# PLANNED PHY PG PROTOTYPE ONLY: no signoff or released-view claim
VERSION 5.8 ;
BUSBITCHARS "[]" ;
DIVIDERCHAR "/" ;
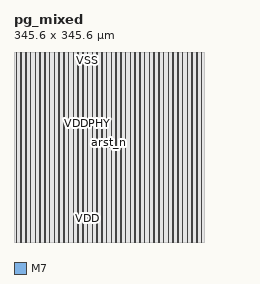
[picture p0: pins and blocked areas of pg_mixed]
MACRO pg_mixed
  CLASS BLOCK ;
  ORIGIN 0 0 ;
  SIZE 345.6000 BY 345.6000 ;
  PIN clk
    DIRECTION INPUT ;
    USE CLOCK ;
    PORT
      LAYER M7 ;
        RECT 172.8160 172.4480 172.8480 173.2160 ;
    END
  END clk
  PIN arst_n
    DIRECTION INPUT ;
    USE SIGNAL ;
    PORT
      LAYER M7 ;
        RECT 172.8160 181.0240 172.8480 181.7920 ;
    END
  END arst_n
  PIN VDD
    DIRECTION INOUT ;
    USE POWER ;
    PORT
      LAYER M7 ;
        RECT 3.9840 0.0000 4.2720 86.3040 ;
      LAYER M7 ;
        RECT 12.6240 0.0000 12.9120 86.3040 ;
      LAYER M7 ;
        RECT 21.2640 0.0000 21.5520 86.3040 ;
      LAYER M7 ;
        RECT 29.9040 0.0000 30.1920 86.3040 ;
      LAYER M7 ;
        RECT 38.5440 0.0000 38.8320 86.3040 ;
      LAYER M7 ;
        RECT 47.1840 0.0000 47.4720 86.3040 ;
      LAYER M7 ;
        RECT 55.8240 0.0000 56.1120 86.3040 ;
      LAYER M7 ;
        RECT 64.4640 0.0000 64.7520 86.3040 ;
      LAYER M7 ;
        RECT 73.1040 0.0000 73.3920 86.3040 ;
      LAYER M7 ;
        RECT 81.7440 0.0000 82.0320 86.3040 ;
      LAYER M7 ;
        RECT 90.3840 0.0000 90.6720 86.3040 ;
      LAYER M7 ;
        RECT 99.0240 0.0000 99.3120 86.3040 ;
      LAYER M7 ;
        RECT 107.6640 0.0000 107.9520 86.3040 ;
      LAYER M7 ;
        RECT 116.3040 0.0000 116.5920 86.3040 ;
      LAYER M7 ;
        RECT 124.9440 0.0000 125.2320 86.3040 ;
      LAYER M7 ;
        RECT 133.5840 0.0000 133.8720 86.3040 ;
      LAYER M7 ;
        RECT 142.2240 0.0000 142.5120 86.3040 ;
      LAYER M7 ;
        RECT 150.8640 0.0000 151.1520 86.3040 ;
      LAYER M7 ;
        RECT 159.5040 0.0000 159.7920 86.3040 ;
      LAYER M7 ;
        RECT 168.1440 0.0000 168.4320 86.3040 ;
      LAYER M7 ;
        RECT 176.7840 0.0000 177.0720 86.3040 ;
      LAYER M7 ;
        RECT 185.4240 0.0000 185.7120 86.3040 ;
      LAYER M7 ;
        RECT 194.0640 0.0000 194.3520 86.3040 ;
      LAYER M7 ;
        RECT 202.7040 0.0000 202.9920 86.3040 ;
      LAYER M7 ;
        RECT 211.3440 0.0000 211.6320 86.3040 ;
      LAYER M7 ;
        RECT 219.9840 0.0000 220.2720 86.3040 ;
      LAYER M7 ;
        RECT 228.6240 0.0000 228.9120 86.3040 ;
      LAYER M7 ;
        RECT 237.2640 0.0000 237.5520 86.3040 ;
      LAYER M7 ;
        RECT 245.9040 0.0000 246.1920 86.3040 ;
      LAYER M7 ;
        RECT 254.5440 0.0000 254.8320 86.3040 ;
      LAYER M7 ;
        RECT 263.1840 0.0000 263.4720 86.3040 ;
      LAYER M7 ;
        RECT 271.8240 0.0000 272.1120 86.3040 ;
      LAYER M7 ;
        RECT 280.4640 0.0000 280.7520 86.3040 ;
      LAYER M7 ;
        RECT 289.1040 0.0000 289.3920 86.3040 ;
      LAYER M7 ;
        RECT 297.7440 0.0000 298.0320 86.3040 ;
      LAYER M7 ;
        RECT 306.3840 0.0000 306.6720 86.3040 ;
      LAYER M7 ;
        RECT 315.0240 0.0000 315.3120 86.3040 ;
      LAYER M7 ;
        RECT 323.6640 0.0000 323.9520 86.3040 ;
      LAYER M7 ;
        RECT 332.3040 0.0000 332.5920 86.3040 ;
      LAYER M7 ;
        RECT 340.9440 0.0000 341.2320 86.3040 ;
    END
  END VDD
  PIN VDDPHY
    DIRECTION INOUT ;
    USE POWER ;
    PORT
      LAYER M7 ;
        RECT 3.9840 86.4000 4.2720 345.6000 ;
      LAYER M7 ;
        RECT 12.6240 86.4000 12.9120 345.6000 ;
      LAYER M7 ;
        RECT 21.2640 86.4000 21.5520 345.6000 ;
      LAYER M7 ;
        RECT 29.9040 86.4000 30.1920 345.6000 ;
      LAYER M7 ;
        RECT 38.5440 86.4000 38.8320 345.6000 ;
      LAYER M7 ;
        RECT 47.1840 86.4000 47.4720 345.6000 ;
      LAYER M7 ;
        RECT 55.8240 86.4000 56.1120 345.6000 ;
      LAYER M7 ;
        RECT 64.4640 86.4000 64.7520 345.6000 ;
      LAYER M7 ;
        RECT 73.1040 86.4000 73.3920 345.6000 ;
      LAYER M7 ;
        RECT 81.7440 86.4000 82.0320 345.6000 ;
      LAYER M7 ;
        RECT 90.3840 86.4000 90.6720 345.6000 ;
      LAYER M7 ;
        RECT 99.0240 86.4000 99.3120 345.6000 ;
      LAYER M7 ;
        RECT 107.6640 86.4000 107.9520 345.6000 ;
      LAYER M7 ;
        RECT 116.3040 86.4000 116.5920 345.6000 ;
      LAYER M7 ;
        RECT 124.9440 86.4000 125.2320 345.6000 ;
      LAYER M7 ;
        RECT 133.5840 86.4000 133.8720 345.6000 ;
      LAYER M7 ;
        RECT 142.2240 86.4000 142.5120 345.6000 ;
      LAYER M7 ;
        RECT 150.8640 86.4000 151.1520 345.6000 ;
      LAYER M7 ;
        RECT 159.5040 86.4000 159.7920 345.6000 ;
      LAYER M7 ;
        RECT 168.1440 86.4000 168.4320 345.6000 ;
      LAYER M7 ;
        RECT 176.7840 86.4000 177.0720 345.6000 ;
      LAYER M7 ;
        RECT 185.4240 86.4000 185.7120 345.6000 ;
      LAYER M7 ;
        RECT 194.0640 86.4000 194.3520 345.6000 ;
      LAYER M7 ;
        RECT 202.7040 86.4000 202.9920 345.6000 ;
      LAYER M7 ;
        RECT 211.3440 86.4000 211.6320 345.6000 ;
      LAYER M7 ;
        RECT 219.9840 86.4000 220.2720 345.6000 ;
      LAYER M7 ;
        RECT 228.6240 86.4000 228.9120 345.6000 ;
      LAYER M7 ;
        RECT 237.2640 86.4000 237.5520 345.6000 ;
      LAYER M7 ;
        RECT 245.9040 86.4000 246.1920 345.6000 ;
      LAYER M7 ;
        RECT 254.5440 86.4000 254.8320 345.6000 ;
      LAYER M7 ;
        RECT 263.1840 86.4000 263.4720 345.6000 ;
      LAYER M7 ;
        RECT 271.8240 86.4000 272.1120 345.6000 ;
      LAYER M7 ;
        RECT 280.4640 86.4000 280.7520 345.6000 ;
      LAYER M7 ;
        RECT 289.1040 86.4000 289.3920 345.6000 ;
      LAYER M7 ;
        RECT 297.7440 86.4000 298.0320 345.6000 ;
      LAYER M7 ;
        RECT 306.3840 86.4000 306.6720 345.6000 ;
      LAYER M7 ;
        RECT 315.0240 86.4000 315.3120 345.6000 ;
      LAYER M7 ;
        RECT 323.6640 86.4000 323.9520 345.6000 ;
      LAYER M7 ;
        RECT 332.3040 86.4000 332.5920 345.6000 ;
      LAYER M7 ;
        RECT 340.9440 86.4000 341.2320 345.6000 ;
    END
  END VDDPHY
  PIN VSS
    DIRECTION INOUT ;
    USE GROUND ;
    PORT
      LAYER M7 ;
        RECT 4.3680 0.0000 4.6560 345.6000 ;
      LAYER M7 ;
        RECT 13.0080 0.0000 13.2960 345.6000 ;
      LAYER M7 ;
        RECT 21.6480 0.0000 21.9360 345.6000 ;
      LAYER M7 ;
        RECT 30.2880 0.0000 30.5760 345.6000 ;
      LAYER M7 ;
        RECT 38.9280 0.0000 39.2160 345.6000 ;
      LAYER M7 ;
        RECT 47.5680 0.0000 47.8560 345.6000 ;
      LAYER M7 ;
        RECT 56.2080 0.0000 56.4960 345.6000 ;
      LAYER M7 ;
        RECT 64.8480 0.0000 65.1360 345.6000 ;
      LAYER M7 ;
        RECT 73.4880 0.0000 73.7760 345.6000 ;
      LAYER M7 ;
        RECT 82.1280 0.0000 82.4160 345.6000 ;
      LAYER M7 ;
        RECT 90.7680 0.0000 91.0560 345.6000 ;
      LAYER M7 ;
        RECT 99.4080 0.0000 99.6960 345.6000 ;
      LAYER M7 ;
        RECT 108.0480 0.0000 108.3360 345.6000 ;
      LAYER M7 ;
        RECT 116.6880 0.0000 116.9760 345.6000 ;
      LAYER M7 ;
        RECT 125.3280 0.0000 125.6160 345.6000 ;
      LAYER M7 ;
        RECT 133.9680 0.0000 134.2560 345.6000 ;
      LAYER M7 ;
        RECT 142.6080 0.0000 142.8960 345.6000 ;
      LAYER M7 ;
        RECT 151.2480 0.0000 151.5360 345.6000 ;
      LAYER M7 ;
        RECT 159.8880 0.0000 160.1760 345.6000 ;
      LAYER M7 ;
        RECT 168.5280 0.0000 168.8160 345.6000 ;
      LAYER M7 ;
        RECT 177.1680 0.0000 177.4560 345.6000 ;
      LAYER M7 ;
        RECT 185.8080 0.0000 186.0960 345.6000 ;
      LAYER M7 ;
        RECT 194.4480 0.0000 194.7360 345.6000 ;
      LAYER M7 ;
        RECT 203.0880 0.0000 203.3760 345.6000 ;
      LAYER M7 ;
        RECT 211.7280 0.0000 212.0160 345.6000 ;
      LAYER M7 ;
        RECT 220.3680 0.0000 220.6560 345.6000 ;
      LAYER M7 ;
        RECT 229.0080 0.0000 229.2960 345.6000 ;
      LAYER M7 ;
        RECT 237.6480 0.0000 237.9360 345.6000 ;
      LAYER M7 ;
        RECT 246.2880 0.0000 246.5760 345.6000 ;
      LAYER M7 ;
        RECT 254.9280 0.0000 255.2160 345.6000 ;
      LAYER M7 ;
        RECT 263.5680 0.0000 263.8560 345.6000 ;
      LAYER M7 ;
        RECT 272.2080 0.0000 272.4960 345.6000 ;
      LAYER M7 ;
        RECT 280.8480 0.0000 281.1360 345.6000 ;
      LAYER M7 ;
        RECT 289.4880 0.0000 289.7760 345.6000 ;
      LAYER M7 ;
        RECT 298.1280 0.0000 298.4160 345.6000 ;
      LAYER M7 ;
        RECT 306.7680 0.0000 307.0560 345.6000 ;
      LAYER M7 ;
        RECT 315.4080 0.0000 315.6960 345.6000 ;
      LAYER M7 ;
        RECT 324.0480 0.0000 324.3360 345.6000 ;
      LAYER M7 ;
        RECT 332.6880 0.0000 332.9760 345.6000 ;
      LAYER M7 ;
        RECT 341.3280 0.0000 341.6160 345.6000 ;
    END
  END VSS
  OBS
    LAYER M1 ;
      RECT 0 0 345.6000 345.6000 ;
    LAYER M2 ;
      RECT 0 0 345.6000 345.6000 ;
    LAYER M3 ;
      RECT 0 0 345.6000 345.6000 ;
    LAYER M4 ;
      RECT 0 0 345.6000 345.6000 ;
    LAYER M5 ;
      RECT 0 0 345.6000 345.6000 ;
    LAYER M6 ;
      RECT 0 0 345.6000 345.6000 ;
    LAYER M7 ;
      RECT 0.0000 0.0000 3.9840 345.6000 ;
      RECT 4.2720 0.0000 4.3680 345.6000 ;
      RECT 4.6560 0.0000 12.6240 345.6000 ;
      RECT 12.9120 0.0000 13.0080 345.6000 ;
      RECT 13.2960 0.0000 21.2640 345.6000 ;
      RECT 21.5520 0.0000 21.6480 345.6000 ;
      RECT 21.9360 0.0000 29.9040 345.6000 ;
      RECT 30.1920 0.0000 30.2880 345.6000 ;
      RECT 30.5760 0.0000 38.5440 345.6000 ;
      RECT 38.8320 0.0000 38.9280 345.6000 ;
      RECT 39.2160 0.0000 47.1840 345.6000 ;
      RECT 47.4720 0.0000 47.5680 345.6000 ;
      RECT 47.8560 0.0000 55.8240 345.6000 ;
      RECT 56.1120 0.0000 56.2080 345.6000 ;
      RECT 56.4960 0.0000 64.4640 345.6000 ;
      RECT 64.7520 0.0000 64.8480 345.6000 ;
      RECT 65.1360 0.0000 73.1040 345.6000 ;
      RECT 73.3920 0.0000 73.4880 345.6000 ;
      RECT 73.7760 0.0000 81.7440 345.6000 ;
      RECT 82.0320 0.0000 82.1280 345.6000 ;
      RECT 82.4160 0.0000 90.3840 345.6000 ;
      RECT 90.6720 0.0000 90.7680 345.6000 ;
      RECT 91.0560 0.0000 99.0240 345.6000 ;
      RECT 99.3120 0.0000 99.4080 345.6000 ;
      RECT 99.6960 0.0000 107.6640 345.6000 ;
      RECT 107.9520 0.0000 108.0480 345.6000 ;
      RECT 108.3360 0.0000 116.3040 345.6000 ;
      RECT 116.5920 0.0000 116.6880 345.6000 ;
      RECT 116.9760 0.0000 124.9440 345.6000 ;
      RECT 125.2320 0.0000 125.3280 345.6000 ;
      RECT 125.6160 0.0000 133.5840 345.6000 ;
      RECT 133.8720 0.0000 133.9680 345.6000 ;
      RECT 134.2560 0.0000 142.2240 345.6000 ;
      RECT 142.5120 0.0000 142.6080 345.6000 ;
      RECT 142.8960 0.0000 150.8640 345.6000 ;
      RECT 151.1520 0.0000 151.2480 345.6000 ;
      RECT 151.5360 0.0000 159.5040 345.6000 ;
      RECT 159.7920 0.0000 159.8880 345.6000 ;
      RECT 160.1760 0.0000 168.1440 345.6000 ;
      RECT 168.4320 0.0000 168.5280 345.6000 ;
      RECT 168.8160 0.0000 176.7840 345.6000 ;
      RECT 177.0720 0.0000 177.1680 345.6000 ;
      RECT 177.4560 0.0000 185.4240 345.6000 ;
      RECT 185.7120 0.0000 185.8080 345.6000 ;
      RECT 186.0960 0.0000 194.0640 345.6000 ;
      RECT 194.3520 0.0000 194.4480 345.6000 ;
      RECT 194.7360 0.0000 202.7040 345.6000 ;
      RECT 202.9920 0.0000 203.0880 345.6000 ;
      RECT 203.3760 0.0000 211.3440 345.6000 ;
      RECT 211.6320 0.0000 211.7280 345.6000 ;
      RECT 212.0160 0.0000 219.9840 345.6000 ;
      RECT 220.2720 0.0000 220.3680 345.6000 ;
      RECT 220.6560 0.0000 228.6240 345.6000 ;
      RECT 228.9120 0.0000 229.0080 345.6000 ;
      RECT 229.2960 0.0000 237.2640 345.6000 ;
      RECT 237.5520 0.0000 237.6480 345.6000 ;
      RECT 237.9360 0.0000 245.9040 345.6000 ;
      RECT 246.1920 0.0000 246.2880 345.6000 ;
      RECT 246.5760 0.0000 254.5440 345.6000 ;
      RECT 254.8320 0.0000 254.9280 345.6000 ;
      RECT 255.2160 0.0000 263.1840 345.6000 ;
      RECT 263.4720 0.0000 263.5680 345.6000 ;
      RECT 263.8560 0.0000 271.8240 345.6000 ;
      RECT 272.1120 0.0000 272.2080 345.6000 ;
      RECT 272.4960 0.0000 280.4640 345.6000 ;
      RECT 280.7520 0.0000 280.8480 345.6000 ;
      RECT 281.1360 0.0000 289.1040 345.6000 ;
      RECT 289.3920 0.0000 289.4880 345.6000 ;
      RECT 289.7760 0.0000 297.7440 345.6000 ;
      RECT 298.0320 0.0000 298.1280 345.6000 ;
      RECT 298.4160 0.0000 306.3840 345.6000 ;
      RECT 306.6720 0.0000 306.7680 345.6000 ;
      RECT 307.0560 0.0000 315.0240 345.6000 ;
      RECT 315.3120 0.0000 315.4080 345.6000 ;
      RECT 315.6960 0.0000 323.6640 345.6000 ;
      RECT 323.9520 0.0000 324.0480 345.6000 ;
      RECT 324.3360 0.0000 332.3040 345.6000 ;
      RECT 332.5920 0.0000 332.6880 345.6000 ;
      RECT 332.9760 0.0000 340.9440 345.6000 ;
      RECT 341.2320 0.0000 341.3280 345.6000 ;
      RECT 341.6160 0.0000 345.6000 345.6000 ;
      RECT 340.9440 86.3040 341.2320 86.4000 ;
      RECT 332.3040 86.3040 332.5920 86.4000 ;
      RECT 323.6640 86.3040 323.9520 86.4000 ;
      RECT 315.0240 86.3040 315.3120 86.4000 ;
      RECT 306.3840 86.3040 306.6720 86.4000 ;
      RECT 297.7440 86.3040 298.0320 86.4000 ;
      RECT 289.1040 86.3040 289.3920 86.4000 ;
      RECT 280.4640 86.3040 280.7520 86.4000 ;
      RECT 271.8240 86.3040 272.1120 86.4000 ;
      RECT 263.1840 86.3040 263.4720 86.4000 ;
      RECT 254.5440 86.3040 254.8320 86.4000 ;
      RECT 245.9040 86.3040 246.1920 86.4000 ;
      RECT 237.2640 86.3040 237.5520 86.4000 ;
      RECT 228.6240 86.3040 228.9120 86.4000 ;
      RECT 219.9840 86.3040 220.2720 86.4000 ;
      RECT 211.3440 86.3040 211.6320 86.4000 ;
      RECT 202.7040 86.3040 202.9920 86.4000 ;
      RECT 194.0640 86.3040 194.3520 86.4000 ;
      RECT 185.4240 86.3040 185.7120 86.4000 ;
      RECT 176.7840 86.3040 177.0720 86.4000 ;
      RECT 168.1440 86.3040 168.4320 86.4000 ;
      RECT 159.5040 86.3040 159.7920 86.4000 ;
      RECT 150.8640 86.3040 151.1520 86.4000 ;
      RECT 142.2240 86.3040 142.5120 86.4000 ;
      RECT 133.5840 86.3040 133.8720 86.4000 ;
      RECT 124.9440 86.3040 125.2320 86.4000 ;
      RECT 116.3040 86.3040 116.5920 86.4000 ;
      RECT 107.6640 86.3040 107.9520 86.4000 ;
      RECT 99.0240 86.3040 99.3120 86.4000 ;
      RECT 90.3840 86.3040 90.6720 86.4000 ;
      RECT 81.7440 86.3040 82.0320 86.4000 ;
      RECT 73.1040 86.3040 73.3920 86.4000 ;
      RECT 64.4640 86.3040 64.7520 86.4000 ;
      RECT 55.8240 86.3040 56.1120 86.4000 ;
      RECT 47.1840 86.3040 47.4720 86.4000 ;
      RECT 38.5440 86.3040 38.8320 86.4000 ;
      RECT 29.9040 86.3040 30.1920 86.4000 ;
      RECT 21.2640 86.3040 21.5520 86.4000 ;
      RECT 12.6240 86.3040 12.9120 86.4000 ;
      RECT 3.9840 86.3040 4.2720 86.4000 ;
  END
END pg_mixed
END LIBRARY
